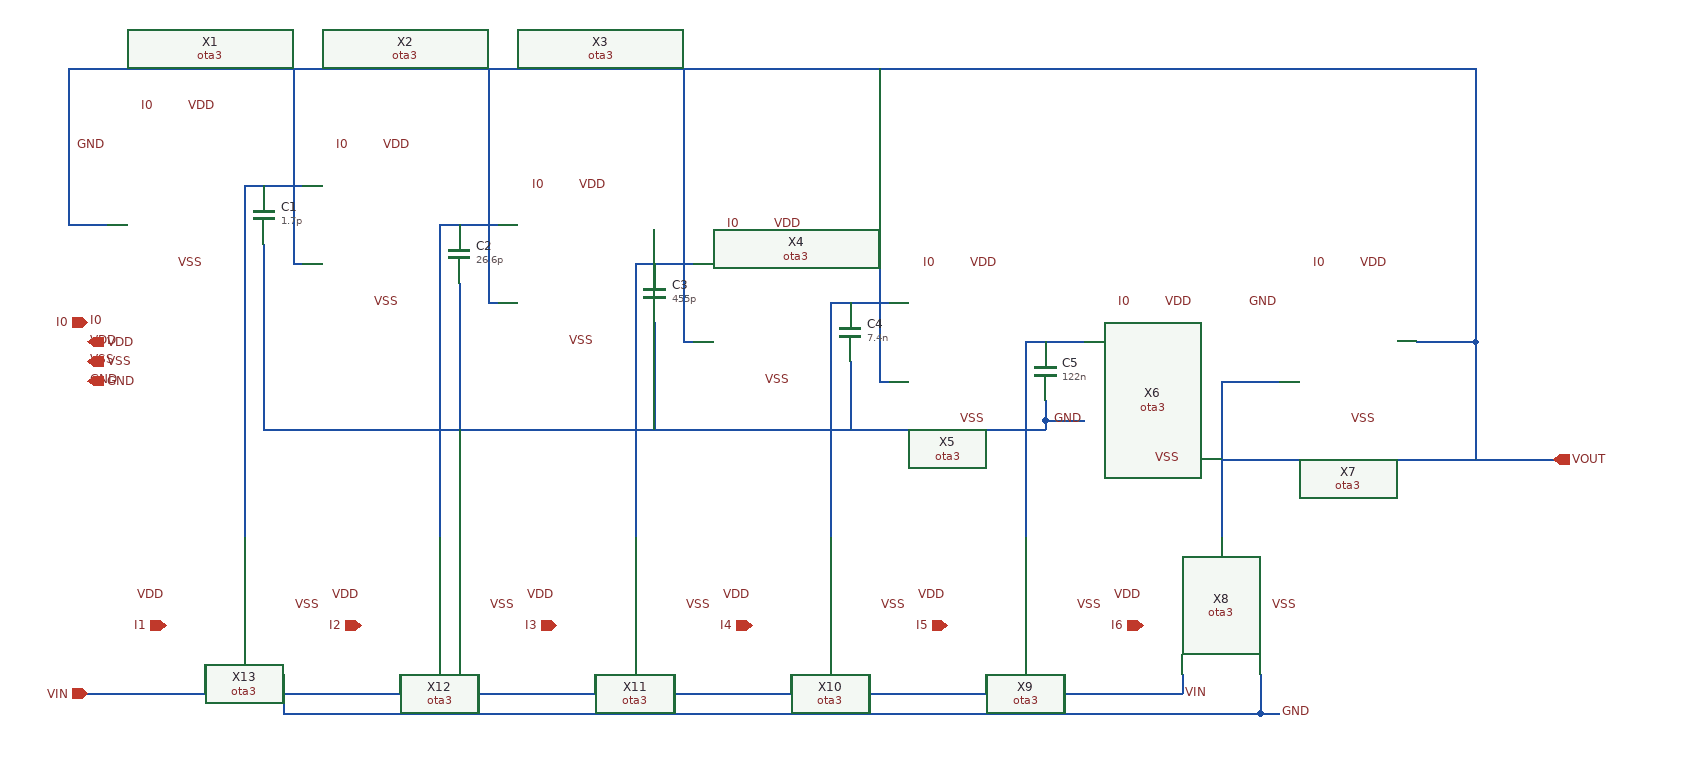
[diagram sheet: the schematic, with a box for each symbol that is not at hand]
v {xschem version=3.4.6RC file_version=1.2
}
G {}
K {}
V {}
S {}
E {}
N 660 -780 720 -780 {
lab=#net1}
N 860 -740 920 -740 {
lab=#net2}
N 1060 -700 1120 -700 {
lab=#net3}
N 1260 -660 1320 -660 {
lab=#net4}
N 1460 -620 1520 -620 {
lab=#net5}
N 1660 -580 1720 -580 {
lab=VOUT}
N 480 -740 520 -740 {
lab=VOUT}
N 480 -900 480 -740 {
lab=VOUT}
N 480 -900 1920 -900 {
lab=VOUT}
N 1860 -620 1920 -620 {
lab=VOUT}
N 1920 -900 1920 -620 {
lab=VOUT}
N 1310 -580 1320 -580 {
lab=VOUT}
N 1310 -900 1310 -580 {
lab=VOUT}
N 1110 -620 1120 -620 {
lab=VOUT}
N 1110 -900 1110 -620 {
lab=VOUT}
N 910 -660 920 -660 {
lab=VOUT}
N 910 -900 910 -660 {
lab=VOUT}
N 710 -700 720 -700 {
lab=VOUT}
N 710 -900 710 -700 {
lab=VOUT}
N 660 -780 660 -420 {
lab=#net1}
N 860 -740 860 -420 {
lab=#net2}
N 1060 -700 1060 -420 {
lab=#net3}
N 1260 -660 1260 -420 {
lab=#net4}
N 1460 -620 1460 -420 {
lab=#net5}
N 1660 -580 1660 -420 {
lab=VOUT}
N 1620 -280 1620 -260 {
lab=VIN}
N 500 -260 1620 -260 {
lab=VIN}
N 620 -280 620 -260 {
lab=VIN}
N 820 -280 820 -260 {
lab=VIN}
N 1020 -280 1020 -260 {
lab=VIN}
N 1220 -280 1220 -260 {
lab=VIN}
N 1420 -280 1420 -260 {
lab=VIN}
N 700 -280 700 -240 {
lab=GND}
N 700 -240 1700 -240 {
lab=GND}
N 1700 -280 1700 -240 {
lab=GND}
N 1500 -280 1500 -240 {
lab=GND}
N 1300 -280 1300 -240 {
lab=GND}
N 1100 -280 1100 -240 {
lab=GND}
N 900 -280 900 -240 {
lab=GND}
N 1700 -240 1720 -240 {
lab=GND}
N 1660 -500 2000 -500 {
lab=VOUT}
N 1920 -620 1920 -500 {
lab=VOUT}
N 1510 -540 1520 -540 {
lab=GND}
N 1480 -540 1510 -540 {
lab=GND}
N 1480 -560 1480 -540 {
lab=GND}
N 1480 -540 1480 -530 {
lab=GND}
N 680 -530 1480 -530 {
lab=GND}
N 680 -720 680 -530 {
lab=GND}
N 880 -680 880 -530 {
lab=GND}
N 1080 -640 1080 -530 {
lab=GND}
N 1280 -600 1280 -530 {
lab=GND}
C {/home/parallels/OTA/ota3.sym} 590 -780 0 0 {name=X1}
C {/home/parallels/OTA/ota3.sym} 790 -740 0 0 {name=X2}
C {/home/parallels/OTA/ota3.sym} 990 -700 0 0 {name=X3}
C {/home/parallels/OTA/ota3.sym} 1190 -660 0 0 {name=X4}
C {/home/parallels/OTA/ota3.sym} 1390 -620 0 0 {name=X5}
C {/home/parallels/OTA/ota3.sym} 1590 -580 0 0 {name=X6}
C {/home/parallels/OTA/ota3.sym} 1790 -620 0 0 {name=X7}
C {/home/parallels/OTA/ota3.sym} 1660 -350 3 0 {name=X8}
C {/home/parallels/OTA/ota3.sym} 1460 -350 3 0 {name=X9}
C {/home/parallels/OTA/ota3.sym} 1260 -350 3 0 {name=X10}
C {/home/parallels/OTA/ota3.sym} 1060 -350 3 0 {name=X11}
C {/home/parallels/OTA/ota3.sym} 860 -350 3 0 {name=X12}
C {/home/parallels/OTA/ota3.sym} 660 -350 3 0 {name=X13}
C {lab_pin.sym} 1720 -240 0 1 {name=p1 sig_type=std_logic lab=GND}
C {lab_pin.sym} 1620 -260 0 1 {name=p2 sig_type=std_logic lab=VIN}
C {ipin.sym} 500 -260 0 0 {name=p3 lab=VIN}
C {ipin.sym} 580 -330 0 0 {name=p4 lab=I1
}
C {ipin.sym} 780 -330 0 0 {name=p5 lab=I2
}
C {ipin.sym} 980 -330 0 0 {name=p10 lab=I3

}
C {ipin.sym} 1180 -330 0 0 {name=p6 lab=I4
}
C {ipin.sym} 1380 -330 0 0 {name=p7 lab=I5
}
C {ipin.sym} 1580 -330 0 0 {name=p8 lab=I6
}
C {lab_pin.sym} 1790 -540 0 1 {name=p9 sig_type=std_logic lab=VSS}
C {lab_pin.sym} 1590 -500 0 1 {name=p11 sig_type=std_logic lab=VSS}
C {lab_pin.sym} 1390 -540 0 1 {name=p12 sig_type=std_logic lab=VSS}
C {lab_pin.sym} 1190 -580 0 1 {name=p13 sig_type=std_logic lab=VSS}
C {lab_pin.sym} 990 -620 0 1 {name=p14 sig_type=std_logic lab=VSS}
C {lab_pin.sym} 790 -660 0 1 {name=p15 sig_type=std_logic lab=VSS}
C {lab_pin.sym} 590 -700 0 1 {name=p16 sig_type=std_logic lab=VSS}
C {lab_pin.sym} 740 -350 3 1 {name=p17 sig_type=std_logic lab=VSS}
C {lab_pin.sym} 1140 -350 3 1 {name=p18 sig_type=std_logic lab=VSS}
C {lab_pin.sym} 940 -350 3 1 {name=p19 sig_type=std_logic lab=VSS}
C {lab_pin.sym} 1340 -350 3 1 {name=p20 sig_type=std_logic lab=VSS}
C {lab_pin.sym} 1540 -350 3 1 {name=p21 sig_type=std_logic lab=VSS}
C {lab_pin.sym} 1740 -350 3 1 {name=p22 sig_type=std_logic lab=VSS}
C {lab_pin.sym} 580 -360 3 1 {name=p23 sig_type=std_logic lab=VDD}
C {lab_pin.sym} 780 -360 3 1 {name=p24 sig_type=std_logic lab=VDD}
C {lab_pin.sym} 980 -360 3 1 {name=p25 sig_type=std_logic lab=VDD}
C {lab_pin.sym} 1180 -360 3 1 {name=p26 sig_type=std_logic lab=VDD}
C {lab_pin.sym} 1380 -360 3 1 {name=p27 sig_type=std_logic lab=VDD}
C {lab_pin.sym} 1580 -360 3 1 {name=p28 sig_type=std_logic lab=VDD}
C {lab_pin.sym} 600 -860 0 1 {name=p29 sig_type=std_logic lab=VDD}
C {lab_pin.sym} 800 -820 0 1 {name=p30 sig_type=std_logic lab=VDD}
C {lab_pin.sym} 1000 -780 0 1 {name=p31 sig_type=std_logic lab=VDD}
C {lab_pin.sym} 1200 -740 0 1 {name=p32 sig_type=std_logic lab=VDD}
C {lab_pin.sym} 1400 -700 0 1 {name=p33 sig_type=std_logic lab=VDD}
C {lab_pin.sym} 1600 -660 0 1 {name=p34 sig_type=std_logic lab=VDD}
C {lab_pin.sym} 1800 -700 0 1 {name=p35 sig_type=std_logic lab=VDD}
C {lab_pin.sym} 1770 -700 1 0 {name=p36 sig_type=std_logic lab=I0}
C {lab_pin.sym} 1570 -660 1 0 {name=p37 sig_type=std_logic lab=I0}
C {lab_pin.sym} 1370 -700 1 0 {name=p38 sig_type=std_logic lab=I0}
C {lab_pin.sym} 1170 -740 1 0 {name=p39 sig_type=std_logic lab=I0}
C {lab_pin.sym} 970 -780 1 0 {name=p40 sig_type=std_logic lab=I0}
C {lab_pin.sym} 770 -820 1 0 {name=p41 sig_type=std_logic lab=I0}
C {lab_pin.sym} 570 -860 1 0 {name=p42 sig_type=std_logic lab=I0}
C {lab_pin.sym} 500 -640 2 0 {name=p43 sig_type=std_logic lab=I0}
C {lab_pin.sym} 500 -620 0 1 {name=p44 sig_type=std_logic lab=VDD}
C {lab_pin.sym} 500 -600 0 1 {name=p45 sig_type=std_logic lab=VSS}
C {lab_pin.sym} 500 -580 0 1 {name=p46 sig_type=std_logic lab=GND}
C {lab_pin.sym} 1520 -540 0 0 {name=p47 sig_type=std_logic lab=GND}
C {lab_pin.sym} 1720 -660 0 0 {name=p48 sig_type=std_logic lab=GND}
C {lab_pin.sym} 520 -820 0 0 {name=p49 sig_type=std_logic lab=GND}
C {ipin.sym} 500 -640 0 0 {name=p50 lab=I0
}
C {iopin.sym} 500 -620 0 1 {name=p51 lab=VDD}
C {iopin.sym} 500 -600 0 1 {name=p52 lab=VSS}
C {iopin.sym} 500 -580 0 1 {name=p53 lab=GND}
C {opin.sym} 2000 -500 0 0 {name=p54 lab=VOUT}
C {capa.sym} 680 -750 0 0 {name=C1
m=1
value=1.7p
footprint=1206
device="ceramic capacitor"}
C {capa.sym} 880 -710 0 0 {name=C2
m=1
value=26.6p
footprint=1206
device="ceramic capacitor"}
C {capa.sym} 1080 -670 0 0 {name=C3
m=1
value=455p
footprint=1206
device="ceramic capacitor"}
C {capa.sym} 1280 -630 0 0 {name=C4
m=1
value=7.4n
footprint=1206
device="ceramic capacitor"}
C {capa.sym} 1480 -590 0 0 {name=C5
m=1
value=122n
footprint=1206
device="ceramic capacitor"}
